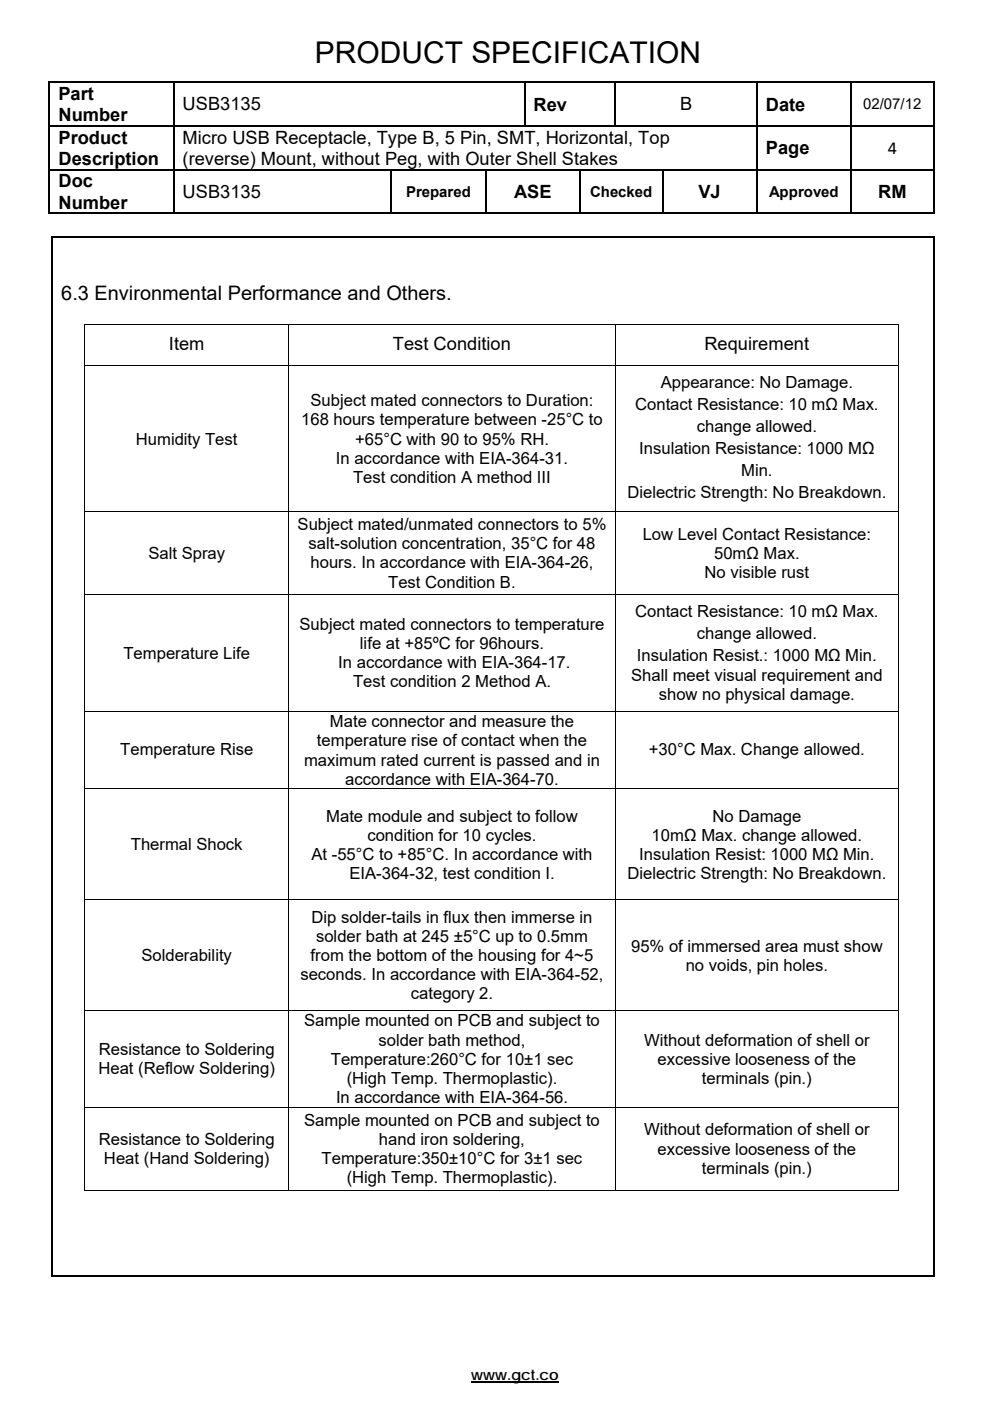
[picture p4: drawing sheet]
<svg xmlns="http://www.w3.org/2000/svg" width="210mm" height="297mm" viewBox="0 0 210 297" stroke-linecap="round" stroke-linejoin="round" font-family="sans-serif">
<defs><g id="words">
<text font-size="6.3" x="66.8" y="13.4">PRODUCT SPECIFICATION</text>
<text font-size="4.2" x="13" y="63.6">6.3 Environmental Performance and Others.</text>
<g font-size="3.9">
<text x="12.4" y="21.2">Part</text>
<text x="38.7" y="23.4">USB3135</text>
<text x="113.2" y="23.4">Rev</text>
<text x="144.3" y="23.4">B</text>
<text x="162.4" y="23.4">Date</text>
<text x="12.4" y="25.7">Number</text>
<text x="12.4" y="30.5">Product</text>
<text x="12.4" y="34.9">Description</text>
<text x="38.7" y="30.5">Micro USB Receptacle, Type B, 5 Pin, SMT, Horizontal, Top</text>
<text x="38.7" y="34.9">(reverse) Mount, without Peg, with Outer Shell Stakes</text>
<text x="162.4" y="32.7">Page</text>
<text x="188.3" y="32.6">4</text>
<text x="12.4" y="39.8">Doc</text>
<text x="38.7" y="42">USB3135</text>
<text x="109" y="42">ASE</text>
<text x="148.1" y="42">VJ</text>
<text x="186.3" y="42">RM</text>
<text x="12.4" y="44.2">Number</text>
<text x="35.8" y="74.2">Item</text>
<text x="83.3" y="74.2">Test Condition</text>
<text x="149.4" y="74.2">Requirement</text>
</g>
<g font-size="3.5">
<text x="140.1" y="82.3">Appearance: No Damage.</text>
<text x="65.8" y="86.2">Subject mated connectors to Duration:</text>
<text x="134.7" y="87">Contact Resistance: 10 mΩ Max.</text>
<text x="28.8" y="94.3">Humidity Test</text>
<text x="63.9" y="90.2">168 hours temperature between -25°C to</text>
<text x="75.3" y="94.3">+65°C with 90 to 95% RH.</text>
<text x="147.8" y="91.7">change allowed.</text>
<text x="71.2" y="98.3">In accordance with EIA-364-31.</text>
<text x="135.6" y="96.3">Insulation Resistance: 1000 MΩ</text>
<text x="157.2" y="101">Min.</text>
<text x="74.9" y="102.4">Test condition A method III</text>
<text x="133.1" y="105.6">Dielectric Strength: No Breakdown.</text>
<text x="63.1" y="112.4">Subject mated/unmated connectors to 5%</text>
<text x="31.5" y="118.5">Salt Spray</text>
<text x="65.4" y="116.4">salt-solution concentration, 35°C for 48</text>
<text x="136.3" y="114.4">Low Level Contact Resistance:</text>
<text x="151.5" y="118.5">50mΩ Max.</text>
<text x="65.9" y="120.5">hours. In accordance with EIA-364-26,</text>
<text x="82.3" y="124.6">Test Condition B.</text>
<text x="149.5" y="122.5">No visible rust</text>
<text x="134.7" y="130.9">Contact Resistance: 10 mΩ Max.</text>
<text x="63.5" y="133.6">Subject mated connectors to temperature</text>
<text x="76.3" y="137.6">life at +85ºC for 96hours.</text>
<text x="147.8" y="135.6">change allowed.</text>
<text x="26.2" y="139.6">Temperature Life</text>
<text x="71.7" y="141.7">In accordance with EIA-364-17.</text>
<text x="135.1" y="140.3">Insulation Resist.: 1000 MΩ Min.</text>
<text x="74.9" y="145.7">Test condition 2 Method A.</text>
<text x="133.9" y="144.3">Shall meet visual requirement and</text>
<text x="139.7" y="148.4">show no physical damage.</text>
<text x="70" y="154.2">Mate connector and measure the</text>
<text x="25.5" y="160">Temperature Rise</text>
<text x="67.2" y="158.3">temperature rise of contact when the</text>
<text x="137.6" y="160">+30°C Max. Change allowed.</text>
<text x="64.5" y="162.3">maximum rated current is passed and in</text>
<text x="73.2" y="166.4">accordance with EIA-364-70.</text>
<text x="69.2" y="174.2">Mate module and subject to follow</text>
<text x="77.9" y="178.2">condition for 10 cycles.</text>
<text x="138.2" y="178.2">10mΩ Max. change allowed.</text>
<text x="151.1" y="174.2">No Damage</text>
<text x="27.7" y="180.3">Thermal Shock</text>
<text x="66.1" y="182.3">At -55°C to +85°C. In accordance with</text>
<text x="135.6" y="182.3">Insulation Resist: 1000 MΩ Min.</text>
<text x="74.1" y="186.4">EIA-364-32, test condition I.</text>
<text x="133.1" y="186.4">Dielectric Strength: No Breakdown.</text>
<text x="66.1" y="195.7">Dip solder-tails in flux then immerse in</text>
<text x="30" y="203.8">Solderability</text>
<text x="65.9" y="203.8">from the bottom of the housing for 4~5</text>
<text x="67" y="199.7">solder bath at 245 ±5°C up to 0.5mm</text>
<text x="133.9" y="201.7">95% of immersed area must show</text>
<text x="63.7" y="207.8">seconds. In accordance with EIA-364-52,</text>
<text x="145.4" y="205.8">no voids, pin holes.</text>
<text x="87.1" y="211.9">category 2.</text>
<text x="64.5" y="217.6">Sample mounted on PCB and subject to</text>
<text x="80.3" y="221.7">solder bath method,</text>
<text x="136.6" y="221.7">Without deformation of shell or</text>
<text x="20.9" y="227.8">Heat (Reflow Soldering)</text>
<text x="21" y="223.7">Resistance to Soldering</text>
<text x="70.2" y="225.8">Temperature:260°C for 10±1 sec</text>
<text x="139.5" y="225.8">excessive looseness of the</text>
<text x="71.3" y="233.9">In accordance with EIA-364-56.</text>
<text x="73.5" y="229.8">(High Temp. Thermoplastic).</text>
<text x="148.9" y="229.8">terminals (pin.)</text>
<text x="64.5" y="238.7">Sample mounted on PCB and subject to</text>
<text x="21" y="242.8">Resistance to Soldering</text>
<text x="80.4" y="242.8">hand iron soldering,</text>
<text x="136.6" y="240.7">Without deformation of shell or</text>
<text x="139.5" y="244.8">excessive looseness of the</text>
<text x="22.1" y="246.8">Heat (Hand Soldering)</text>
<text x="68.2" y="246.8">Temperature:350±10°C for 3±1 sec</text>
<text x="73.5" y="250.9">(High Temp. Thermoplastic).</text>
<text x="148.9" y="248.8">terminals (pin.)</text>
</g>
<g font-size="3.2">
<text x="183.1" y="23.2">02/07/12</text>
<text x="86.1" y="41.7">Prepared</text>
<text x="125.2" y="41.7">Checked</text>
<text x="163.1" y="41.7">Approved</text>
<text x="100" y="292.7">www.gct.co</text>
</g>
</g></defs>
<g fill="#000">
<path d="M10.3 17.2h.4v.4h-.4zM36.7 17.2h.3v.4h-.3zM111.1 17.2h.3v.4h-.3zM130.4 17.2h.3v.4h-.3zM160.4 17.2h.3v.4h-.3zM180.4 17.2h.3v.4h-.3zM197.9 17.2h.3v.4h-.3zM10.3 26.5h.4v.4h-.4zM10.3 35.8h.4v.4h-.4zM36.7 26.5h.3v.4h-.3zM36.7 35.8h.3v.4h-.3zM82.8 35.8h.4v.4h-.4z"/>
<path d="M102.8 35.8h.4v.4h-.4zM122.9 35.8h.3v.4h-.3zM140.4 35.8h.3v.4h-.3zM160.4 26.5h.3v.4h-.3zM160.4 35.8h.3v.4h-.3zM180.4 26.5h.3v.4h-.3zM180.4 35.8h.3v.4h-.3zM197.9 26.5h.3v.4h-.3zM197.9 35.8h.3v.4h-.3zM10.9 50.1h.4v.4h-.4zM197.9 45.1h.3v.3h-.3zM197.9 50.1h.3v.4h-.3z"/>
<path d="M17.9 68.7h.2v.2h-.2zM190.5 68.7h.1v.2h-.1zM190.5 252.3h.1v.2h-.1zM197.9 270.4h.3v.3h-.3z"/>
</g>
<g fill="none" stroke="#000" stroke-width=".34">
<path d="M10.3 17.4h26.4M10.5 17.6v8.9M36.8 17.6v8.9M37 17.4h74.1M111.3 17.6v8.9M111.4 17.4h19M130.5 17.6v8.9M130.7 17.4h29.7M160.5 17.6v8.9M160.7 17.4h19.7M180.5 17.6v8.9M180.7 17.4h17.2"/>
<path d="M198 17.6v8.9M10.5 26.9v8.9M10.5 36.2v9.2M10.7 26.7h26M10.7 36h26M36.8 26.9v8.9M36.8 36.2v9.2M37 36h45.8M83 36.2v9.2M83.2 36h19.6M103 36.2v9.2M103.2 36h19.7"/>
<path d="M123 36.2v9.2M123.2 36h17.2M140.5 36.2v9.2M140.7 36h19.7M160.4 26.7h-123.4M160.5 26.9v8.9M160.5 36.2v9.2M160.7 26.7h19.7M160.7 36h19.7M180.5 26.9v8.9M180.5 36.2v9.2M180.7 26.7h17.2"/>
<path d="M180.7 36h17.2M198 26.9v8.9M198 36.2v9.2M10.3 45.3h26.4M10.9 50.3h187M11.1 50.5v220.2M37 45.3h45.8M83.2 45.3h19.6M103.2 45.3h19.7M123.2 45.3h17.2M140.7 45.3h19.7M160.7 45.3h19.7"/>
<path d="M180.7 45.3h17.2M198 50.5v220.2M10.9 270.6h187"/>
</g>
<path d="M100 293.1h18.5" fill="none" stroke="#000" stroke-width=".28"/>
<g fill="none" stroke="#000" stroke-width=".21">
<path d="M17.9 68.8h172.7M17.9 77.6h172.7M18 68.9v8.6M18 77.6v30.8M61.2 68.9v8.6M61.2 77.6v30.8M130.5 68.9v8.6M130.5 77.6v30.8M190.5 68.9v8.6M190.5 77.6v30.8M17.9 108.5h172.7M18 108.6v17.3"/>
<path d="M61.2 108.6v17.3M130.5 108.6v17.3M190.5 108.6v17.3M17.9 125.9h172.7M18 126v24.8M61.2 126v24.8M130.5 126v24.8M190.5 126v24.8M17.9 150.9h172.7M18 150.9v16.3M61.2 150.9v16.3M130.5 150.9v16.3"/>
<path d="M190.5 150.9v16.3M17.9 167.3h172.7M18 167.3v23.4M61.2 167.3v23.4M130.5 167.3v23.4M190.5 167.3v23.4M17.9 190.8h172.7M18 190.9v23.3M61.2 190.9v23.3M130.5 190.9v23.3M190.5 190.9v23.3M17.9 214.3h172.7"/>
<path d="M18 214.4v20.3M61.2 214.4v20.3M130.5 214.4v20.3M190.5 214.4v20.3M17.9 234.8h172.7M18 234.8v17.7M61.2 234.8v17.7M130.5 234.8v17.7M190.5 234.8v17.7M17.9 252.4h43.2M61.3 252.4h69.2M130.6 252.4h59.9"/>
</g>
<use href="#words"/>
</svg>
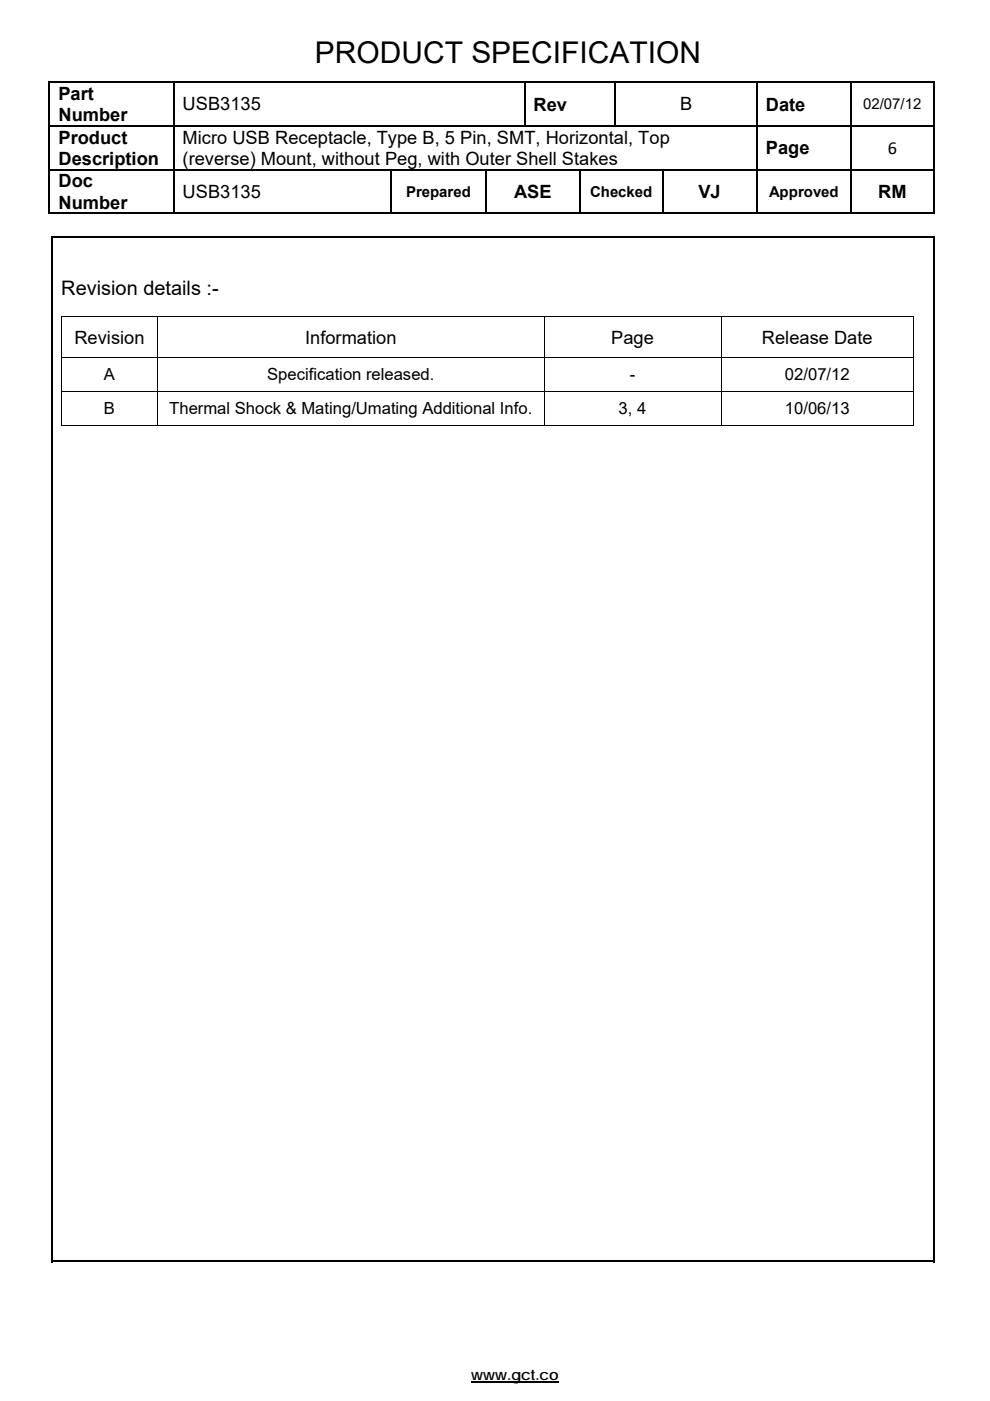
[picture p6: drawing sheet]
<svg xmlns="http://www.w3.org/2000/svg" width="210mm" height="297mm" viewBox="0 0 210 297" stroke-linecap="round" stroke-linejoin="round" font-family="sans-serif">
<defs><g id="words">
<text font-size="6.3" x="66.8" y="13.4">PRODUCT SPECIFICATION</text>
<text font-size="4.2" x="13" y="62.6">Revision details :-</text>
<g font-size="3.9">
<text x="12.4" y="21.2">Part</text>
<text x="38.7" y="23.4">USB3135</text>
<text x="113.2" y="23.4">Rev</text>
<text x="144.3" y="23.4">B</text>
<text x="162.4" y="23.4">Date</text>
<text x="12.4" y="25.7">Number</text>
<text x="12.4" y="30.5">Product</text>
<text x="12.4" y="34.9">Description</text>
<text x="38.7" y="30.5">Micro USB Receptacle, Type B, 5 Pin, SMT, Horizontal, Top</text>
<text x="38.7" y="34.9">(reverse) Mount, without Peg, with Outer Shell Stakes</text>
<text x="162.4" y="32.7">Page</text>
<text x="188.3" y="32.6">6</text>
<text x="12.4" y="39.8">Doc</text>
<text x="38.7" y="42">USB3135</text>
<text x="109" y="42">ASE</text>
<text x="148.1" y="42">VJ</text>
<text x="186.3" y="42">RM</text>
<text x="12.4" y="44.2">Number</text>
<text x="15.8" y="72.8">Revision</text>
<text x="64.7" y="72.8">Information</text>
<text x="129.7" y="72.8">Page</text>
<text x="161.6" y="72.8">Release Date</text>
</g>
<g font-size="3.5">
<text x="22.1" y="80.6">A</text>
<text x="56.7" y="80.6">Specification released.</text>
<text x="133.6" y="80.6">-</text>
<text x="166.5" y="80.6">02/07/12</text>
<text x="22.1" y="87.8">B</text>
<text x="35.9" y="87.8">Thermal Shock &amp; Mating/Umating Additional Info.</text>
<text x="131.2" y="87.8">3, 4</text>
<text x="166.5" y="87.8">10/06/13</text>
</g>
<g font-size="3.2">
<text x="183.1" y="23.2">02/07/12</text>
<text x="86.1" y="41.7">Prepared</text>
<text x="125.2" y="41.7">Checked</text>
<text x="163.1" y="41.7">Approved</text>
<text x="100" y="292.7">www.gct.co</text>
</g>
</g></defs>
<g fill="#000">
<path d="M10.3 17.2h.4v.4h-.4zM36.7 17.2h.3v.4h-.3zM111.1 17.2h.3v.4h-.3zM130.4 17.2h.3v.4h-.3zM160.4 17.2h.3v.4h-.3zM180.4 17.2h.3v.4h-.3zM197.9 17.2h.3v.4h-.3zM10.3 26.5h.4v.4h-.4zM10.3 35.8h.4v.4h-.4zM36.7 26.5h.3v.4h-.3zM36.7 35.8h.3v.4h-.3zM82.8 35.8h.4v.4h-.4z"/>
<path d="M102.8 35.8h.4v.4h-.4zM122.9 35.8h.3v.4h-.3zM140.4 35.8h.3v.4h-.3zM160.4 26.5h.3v.4h-.3zM160.4 35.8h.3v.4h-.3zM180.4 26.5h.3v.4h-.3zM180.4 35.8h.3v.4h-.3zM197.9 26.5h.3v.4h-.3zM197.9 35.8h.3v.4h-.3zM10.9 50.1h.4v.4h-.4zM197.9 45.1h.3v.3h-.3zM197.9 50.1h.3v.4h-.3z"/>
<path d="M13 67.1h.2v.2h-.2zM193.7 67.1h.2v.2h-.2zM193.7 90h.2v.2h-.2zM197.9 267.3h.3v.3h-.3z"/>
</g>
<g fill="none" stroke="#000" stroke-width=".34">
<path d="M10.3 17.4h26.4M10.5 17.6v8.9M36.8 17.6v8.9M37 17.4h74.1M111.3 17.6v8.9M111.4 17.4h19M130.5 17.6v8.9M130.7 17.4h29.7M160.5 17.6v8.9M160.7 17.4h19.7M180.5 17.6v8.9M180.7 17.4h17.2"/>
<path d="M198 17.6v8.9M10.5 26.9v8.9M10.5 36.2v9.2M10.7 26.7h26M10.7 36h26M36.8 26.9v8.9M36.8 36.2v9.2M37 36h45.8M83 36.2v9.2M83.2 36h19.6M103 36.2v9.2M103.2 36h19.7"/>
<path d="M123 36.2v9.2M123.2 36h17.2M140.5 36.2v9.2M140.7 36h19.7M160.4 26.7h-123.4M160.5 26.9v8.9M160.5 36.2v9.2M160.7 26.7h19.7M160.7 36h19.7M180.5 26.9v8.9M180.5 36.2v9.2M180.7 26.7h17.2"/>
<path d="M180.7 36h17.2M198 26.9v8.9M198 36.2v9.2M10.3 45.3h26.4M10.9 50.3h187M11.1 50.5v217.1M37 45.3h45.8M83.2 45.3h19.6M103.2 45.3h19.7M123.2 45.3h17.2M140.7 45.3h19.7M160.7 45.3h19.7"/>
<path d="M180.7 45.3h17.2M198 50.5v217.1M10.9 267.5h187"/>
</g>
<path d="M100 293.1h18.5" fill="none" stroke="#000" stroke-width=".28"/>
<g fill="none" stroke="#000" stroke-width=".21">
<path d="M13 67.2h180.9M13 75.8h180.9M13.1 67.3v8.4M13.1 75.8v7M33.4 67.3v8.4M33.4 75.8v7M115.4 67.3v8.4M115.4 75.8v7M152.9 67.3v8.4M152.9 75.8v7M193.8 67.3v8.4M193.8 75.8v7"/>
<path d="M13 82.9h180.9M13 90.1h20.3M13.1 83v7.2M33.4 83v7.2M33.5 90.1h81.9M115.4 83v7.2M115.5 90.1h37.3M152.9 83v7.2M153 90.1h40.7M193.8 83v7.2"/>
</g>
<use href="#words"/>
</svg>
